VERSION 5.7 ;
  NOWIREEXTENSIONATPIN ON ;
  DIVIDERCHAR "/" ;
  BUSBITCHARS "[]" ;
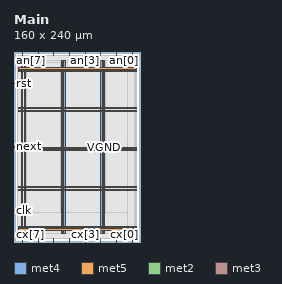
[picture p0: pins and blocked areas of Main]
MACRO Main
  CLASS BLOCK ;
  FOREIGN Main ;
  ORIGIN 0.000 0.000 ;
  SIZE 160.000 BY 240.000 ;
  PIN VGND
    DIRECTION INOUT ;
    USE GROUND ;
    PORT
      LAYER met4 ;
        RECT 13.020 10.640 14.620 228.720 ;
    END
    PORT
      LAYER met4 ;
        RECT 63.020 10.640 64.620 228.720 ;
    END
    PORT
      LAYER met4 ;
        RECT 113.020 10.640 114.620 228.720 ;
    END
    PORT
      LAYER met5 ;
        RECT 5.280 18.380 154.340 19.980 ;
    END
    PORT
      LAYER met5 ;
        RECT 5.280 68.380 154.340 69.980 ;
    END
    PORT
      LAYER met5 ;
        RECT 5.280 118.380 154.340 119.980 ;
    END
    PORT
      LAYER met5 ;
        RECT 5.280 168.380 154.340 169.980 ;
    END
    PORT
      LAYER met5 ;
        RECT 5.280 218.380 154.340 219.980 ;
    END
  END VGND
  PIN VPWR
    DIRECTION INOUT ;
    USE POWER ;
    PORT
      LAYER met4 ;
        RECT 9.720 10.640 11.320 228.720 ;
    END
    PORT
      LAYER met4 ;
        RECT 59.720 10.640 61.320 228.720 ;
    END
    PORT
      LAYER met4 ;
        RECT 109.720 10.640 111.320 228.720 ;
    END
    PORT
      LAYER met5 ;
        RECT 5.280 15.080 154.340 16.680 ;
    END
    PORT
      LAYER met5 ;
        RECT 5.280 65.080 154.340 66.680 ;
    END
    PORT
      LAYER met5 ;
        RECT 5.280 115.080 154.340 116.680 ;
    END
    PORT
      LAYER met5 ;
        RECT 5.280 165.080 154.340 166.680 ;
    END
    PORT
      LAYER met5 ;
        RECT 5.280 215.080 154.340 216.680 ;
    END
  END VPWR
  PIN an[0]
    DIRECTION OUTPUT ;
    USE SIGNAL ;
    ANTENNADIFFAREA 0.340600 ;
    PORT
      LAYER met2 ;
        RECT 149.130 236.000 149.410 240.000 ;
    END
  END an[0]
  PIN an[1]
    DIRECTION OUTPUT ;
    USE SIGNAL ;
    ANTENNADIFFAREA 0.340600 ;
    PORT
      LAYER met2 ;
        RECT 129.350 236.000 129.630 240.000 ;
    END
  END an[1]
  PIN an[2]
    DIRECTION OUTPUT ;
    USE SIGNAL ;
    ANTENNADIFFAREA 0.340600 ;
    PORT
      LAYER met2 ;
        RECT 109.570 236.000 109.850 240.000 ;
    END
  END an[2]
  PIN an[3]
    DIRECTION OUTPUT ;
    USE SIGNAL ;
    ANTENNADIFFAREA 0.340600 ;
    PORT
      LAYER met2 ;
        RECT 89.790 236.000 90.070 240.000 ;
    END
  END an[3]
  PIN an[4]
    DIRECTION OUTPUT ;
    USE SIGNAL ;
    ANTENNADIFFAREA 0.340600 ;
    PORT
      LAYER met2 ;
        RECT 70.010 236.000 70.290 240.000 ;
    END
  END an[4]
  PIN an[5]
    DIRECTION OUTPUT ;
    USE SIGNAL ;
    ANTENNADIFFAREA 0.340600 ;
    PORT
      LAYER met2 ;
        RECT 50.230 236.000 50.510 240.000 ;
    END
  END an[5]
  PIN an[6]
    DIRECTION OUTPUT ;
    USE SIGNAL ;
    ANTENNADIFFAREA 0.340600 ;
    PORT
      LAYER met2 ;
        RECT 30.450 236.000 30.730 240.000 ;
    END
  END an[6]
  PIN an[7]
    DIRECTION OUTPUT ;
    USE SIGNAL ;
    ANTENNADIFFAREA 0.340600 ;
    PORT
      LAYER met2 ;
        RECT 10.670 236.000 10.950 240.000 ;
    END
  END an[7]
  PIN clk
    DIRECTION INPUT ;
    USE SIGNAL ;
    ANTENNAGATEAREA 0.852000 ;
    PORT
      LAYER met3 ;
        RECT 0.000 39.480 4.000 40.080 ;
    END
  END clk
  PIN cx[0]
    DIRECTION OUTPUT ;
    USE SIGNAL ;
    PORT
      LAYER met2 ;
        RECT 149.130 0.000 149.410 4.000 ;
    END
  END cx[0]
  PIN cx[1]
    DIRECTION OUTPUT ;
    USE SIGNAL ;
    ANTENNADIFFAREA 0.340600 ;
    PORT
      LAYER met2 ;
        RECT 129.350 0.000 129.630 4.000 ;
    END
  END cx[1]
  PIN cx[2]
    DIRECTION OUTPUT ;
    USE SIGNAL ;
    ANTENNADIFFAREA 0.340600 ;
    PORT
      LAYER met2 ;
        RECT 109.570 0.000 109.850 4.000 ;
    END
  END cx[2]
  PIN cx[3]
    DIRECTION OUTPUT ;
    USE SIGNAL ;
    ANTENNADIFFAREA 0.340600 ;
    PORT
      LAYER met2 ;
        RECT 89.790 0.000 90.070 4.000 ;
    END
  END cx[3]
  PIN cx[4]
    DIRECTION OUTPUT ;
    USE SIGNAL ;
    ANTENNADIFFAREA 0.340600 ;
    PORT
      LAYER met2 ;
        RECT 70.010 0.000 70.290 4.000 ;
    END
  END cx[4]
  PIN cx[5]
    DIRECTION OUTPUT ;
    USE SIGNAL ;
    ANTENNADIFFAREA 0.340600 ;
    PORT
      LAYER met2 ;
        RECT 50.230 0.000 50.510 4.000 ;
    END
  END cx[5]
  PIN cx[6]
    DIRECTION OUTPUT ;
    USE SIGNAL ;
    ANTENNADIFFAREA 0.340600 ;
    PORT
      LAYER met2 ;
        RECT 30.450 0.000 30.730 4.000 ;
    END
  END cx[6]
  PIN cx[7]
    DIRECTION OUTPUT ;
    USE SIGNAL ;
    ANTENNADIFFAREA 0.340600 ;
    PORT
      LAYER met2 ;
        RECT 10.670 0.000 10.950 4.000 ;
    END
  END cx[7]
  PIN next
    DIRECTION INPUT ;
    USE SIGNAL ;
    ANTENNAGATEAREA 0.126000 ;
    PORT
      LAYER met3 ;
        RECT 0.000 119.720 4.000 120.320 ;
    END
  END next
  PIN rst
    DIRECTION INPUT ;
    USE SIGNAL ;
    ANTENNAGATEAREA 0.159000 ;
    PORT
      LAYER met3 ;
        RECT 0.000 199.960 4.000 200.560 ;
    END
  END rst
  OBS
      LAYER nwell ;
        RECT 5.330 10.795 154.290 228.565 ;
      LAYER li1 ;
        RECT 5.520 10.795 154.100 228.565 ;
      LAYER met1 ;
        RECT 4.210 10.640 154.100 228.720 ;
      LAYER met2 ;
        RECT 4.230 235.720 10.390 236.000 ;
        RECT 11.230 235.720 30.170 236.000 ;
        RECT 31.010 235.720 49.950 236.000 ;
        RECT 50.790 235.720 69.730 236.000 ;
        RECT 70.570 235.720 89.510 236.000 ;
        RECT 90.350 235.720 109.290 236.000 ;
        RECT 110.130 235.720 129.070 236.000 ;
        RECT 129.910 235.720 148.850 236.000 ;
        RECT 149.690 235.720 152.620 236.000 ;
        RECT 4.230 4.280 152.620 235.720 ;
        RECT 4.230 4.000 10.390 4.280 ;
        RECT 11.230 4.000 30.170 4.280 ;
        RECT 31.010 4.000 49.950 4.280 ;
        RECT 50.790 4.000 69.730 4.280 ;
        RECT 70.570 4.000 89.510 4.280 ;
        RECT 90.350 4.000 109.290 4.280 ;
        RECT 110.130 4.000 129.070 4.280 ;
        RECT 129.910 4.000 148.850 4.280 ;
        RECT 149.690 4.000 152.620 4.280 ;
      LAYER met3 ;
        RECT 3.990 200.960 143.250 228.645 ;
        RECT 4.400 199.560 143.250 200.960 ;
        RECT 3.990 120.720 143.250 199.560 ;
        RECT 4.400 119.320 143.250 120.720 ;
        RECT 3.990 40.480 143.250 119.320 ;
        RECT 4.400 39.080 143.250 40.480 ;
        RECT 3.990 10.715 143.250 39.080 ;
      LAYER met4 ;
        RECT 15.935 37.575 59.320 226.945 ;
        RECT 61.720 37.575 62.620 226.945 ;
        RECT 65.020 37.575 109.320 226.945 ;
        RECT 111.720 37.575 112.620 226.945 ;
        RECT 115.020 37.575 143.225 226.945 ;
  END
END Main
END LIBRARY

